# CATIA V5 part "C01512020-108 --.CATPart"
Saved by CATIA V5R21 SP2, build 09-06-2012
Part number: C01512020-108
Revision: ---
Description: PROPRIETARY NOTICE (do not delete / modify)  ***************************************************************************************************  LA SOCIETE EN COMMANDITE  AIRBUS CANADA  ("AIRBUS CANADA")  PAR  L'INTERMEDIAIRE  DE  SES  DIVISIONS  ET/OU  FILIALES  CORPORATIVES,  FOURNIT  LES PRESENTES  INFORMATIONS  AU  GOUVERNEMENT  A  TITRE CONFIDENTIEL. CES  INFORMATIONS ONT UNE TENEUR CONFIDENTIELLE,  AVEC DROITS DE PROPRIETE,  ET NOUS LES CONSIDERONS  EXCLUS  DE   L'APPLICATION  DE  LA LOI SUR L'ACCES A L'INFORMATION  (CANADA),  LES  LOIS  SUR  L'ACCES  A  L'INFORMATION  EUROPEENNES,  LE FREEDOM OF INFORMATION ACT (ETATS-UNIS) ET D'AUTRES LOIS SEMBLABLES. ELLES  PEUVENT  AUSSI  CONSTITUER DES SECRETS INDUSTRIELS DE NOTRE SOCIETE OU DE TIERCES PARTIES. LA DIVULGATION  PUBLIQUE  DE CES  INFORMATIONS NUIRAIT A AIRBUS CANADA OU A DES TIERCES PARTIES.  CES INFORMATIONS PEUVENT EGALEMENT CONTENIR  DES DONNEES QUI SONT CONTROLEE PAR DES LOIS DE CONTROLE DES EXPORTATIONS DU CANADA, L’EUROPE OU LES  ETATS-  UNIS. TOUTE EXPORTATION OU REEXPORTATION DE DONNEES CONTROLEES SANS AUTORISATION EST STRICTEMENT INTERDITE.  TOUTE INTENTION DE LES DIVULGUER EN TOUT OU EN PARTIE DEVRA ETRE SIGNIFIEE A L'AVANCE ET PAR ECRIT AU VICE-  PRESIDENT, SERVICES JURIDIQUES ET CONFORMITE ET SECRETAIRE CORPORATIF D'AIRBUS CANADA.    AIRBUS CANADA LIMITED PARTNERSHIP  ("AIRBUS CANADA"),  BY ITS AFFILIATES AND/OR SUBSIDIARIES, PROVIDES THIS  INFORMATION TO THE GOVERNMENT IN CONFIDENCE. THIS IS PROPRIETARY CONFIDENTIAL INFORMATION WHICH WE CONSIDER  EXCLUDED  FROM  THE  APPLICATION OF THE ACCESS TO INFORMATION ACT (CANADA),  THE FREEDOM OF INFORMATION ACT  (U.S.A.),  THE ACCESS TO INFORMATION LAWS IN EUROPE, AND OTHER SIMILAR LEGISLATION. AND MAY ALSO CONSTITUTE  TRADE SECRETS OF OUR  COMPANY OR THIRD PARTIES.  PUBLIC  RELEASE  OF  THIS INFORMATION  WOULD BE HARMFUL TO  AIRBUS CANADA OR THIRD PARTIES.  THIS  INFORMATION  MAY  ALSO  CONTAIN DATA THAT IS CONTROLLED BY CANADIAN,  EUROPEAN, OR U.S.A. EXPORT CONTROL LAWS. ANY UNAUTHORIZED EXPORT OR RE-EXPORT OF ANY EXPORT CONTROLLED DATA  IS STRICTLY PROHIBITED  ANY INTENTION TO DISCLOSE SUCH INFORMATION,  OR  PART THEREOF,  MUST BE NOTIFIED IN  ADVANCE AND IN WRITING TO THE VICE PRESIDENT, LEGAL AND COMPLIANCE AND CORPORATE SECRETARY OF AIRBUS CANADA.        LES RENSEIGNEMENTS,  LES DONNEES  ET  DESSINS  TECHNIQUES  DIVULGUES  DANS  LES PRESENTES SONT LA PROPRIETE  EXCLUSIVE DE LA SOCIETE EN COMMANDITE AIRBUS CANADA ("AIRBUS CANADA") OU COMPORTENT DES DROITS DE PROPRIETE  APPARTENANT  A  AUTRUI ET NE PEUVENT ETRE DIVULGUES  A  QUICONQUE  NI  UTILISES PAR QUI QUE CE SOIT SANS LE  CONSENTEMENT  ECRIT  D’AIRBUS  CANADA.  LE DETENTEUR DES  PRESENTES  S'ENGAGE, DANS TOUTES CIRCONSTANCES, A  GARDER CONFIDENTIELS LES DONNEES ET DESSINS TECHNIQUES QU'ELLES CONTIENNENT.   CE QUI PRECEDE NE S'APPLIQUE  PAS  AUX PERSONNES  QUI  ONT DES DROITS DE PROPRIETE SUR CES RENSEIGNEMENTS,  DONNEES TECHNIQUES ET DESSINS  DANS LA MESURE OU CES DROITS EXISTENT.    THE INFORMATION,  TECHNICAL DATA  AND  DESIGNS DISCLOSED HEREIN ARE THE EXCLUSIVE PROPERTY OF AIRBUS CANADA  LIMITED PARTNERSHIP  ("AIRBUS CANADA")  OR  CONTAIN PROPRIETARY RIGHTS OF OTHERS  AND ARE NOT TO BE USED OR  DISCLOSED  TO  OTHERS WITHOUT THE WRITTEN CONSENT OF AIRBUS CANADA.  THE RECIPIENT OF THIS DOCUMENT, BY ITS  RETENTION  AND  USE  AGREES TO  HOLD  IN  CONFIDENCE  THE  TECHNICAL DATA AND DESIGNS CONTAINED HEREIN. THE  FOREGOING SHALL NOT APPLY TO PERSONS HAVING PROPRIETARY RIGHTS TO SUCH INFORMATION,  TECHNICAL DATA OR SUCH  DESIGNS TO THE EXTENT THAT SUCH RIGHTS EXIST.    Copyright 2020 Airbus Canada Limited Partnership. All Rights Reserved.  ***********************************
Property "Title": "LEVER, GIRT BAR, PASS SVCE DR"
Property "Dataset Type": "DETAIL"
Property "Supplier Name And CAGE Code": "AIRBUS CANADA LIMITED PARTNERSHIP L0J48"
Property "Major Supplier Code": "LP"
Property "3D Only": "N/A"
Property "Material Form": "BAR - FLAT"
Property "Finish Code": "S010"
Property "PCCN": "2"
Property "Organization": "DESIGN"
Property "Design Authority Program": "BD-500"
Property "Color Coded": "N/A"
Property "Thickness": 1.25
Property "Inside Diameter": 0
Property "Outside Diameter": 0
Property "Length": 0
Property "Width": 2.5
Property "Wall": 0
Property "Wire Gauge": "-"
Property "Alloy": "15-5PH"
Property "Final Condition": "H1025"
Property "Density": "N/A"
Property "Form": "N/A"
Property "Grade/Composition": "N/A"
Property "Material Class": "N/A"
Property "Mesh Cell Size": "N/A"
Property "Standard Spec Die": "N/A"
Property "Type": "N/A"
Property "Style": "N/A"
Property "MFG Process": "MACHINED"
Property "Material Specification Production": "AMS5659"
Property "Material Description Production": "CRES"
Property "Dimensions": "DIMENSIONS ARE IN INCHES"
Property "Roughness": "ALL MACHINED SURFACES 125 Ra MAX"
Property "Eng. Tolerances": "LINEAR .XX= +/-.03; .XXX= +/-.010; ANGULAR= +/-0.5 DEG"
Property "Tool Design Tolerances": "LINEAR .X= +/-.06; .XX= +/-.015; .XXX= +/-.005; .XXXX= +/-.001; ANGULAR= +/-0.5 DEG"
Property "Project": "BA"
Publications: "PartBody"
Material "CRES-PH-15-5-BAR": density 7833.41 kg/m3
Bounding box of the stored display mesh (mm): x -68.58 to 9.804, y -24.091 to 31.359, z -19.096 to 10.921
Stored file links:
  C:\Users\CQQZ006\Desktop\A220钢钛件\舱门\C01512020-108\C01512020-108 --.CATPart
  I:\Standard\Materials\Textures\steel100.jpeg

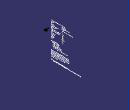
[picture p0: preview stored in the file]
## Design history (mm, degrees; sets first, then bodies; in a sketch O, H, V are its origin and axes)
AxisSystem1 "Absolute Axis System": origin (0, 0, 0), X (1, 0, 0), Y (0, 1, 0), Z (0, 0, 1)
Part_3D_Annotations1 "CATTPSSet"
Body1 "PartBody" (main body)
  Solid1: linked copy from another document
  Symmetry1: ToTransfor Solid1, Reference yz-plane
